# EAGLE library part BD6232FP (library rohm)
H-bridge driver for brush motors Source: http://www.rohm.com/products/databook/motor/pdf/bd623x_series-e.pdf

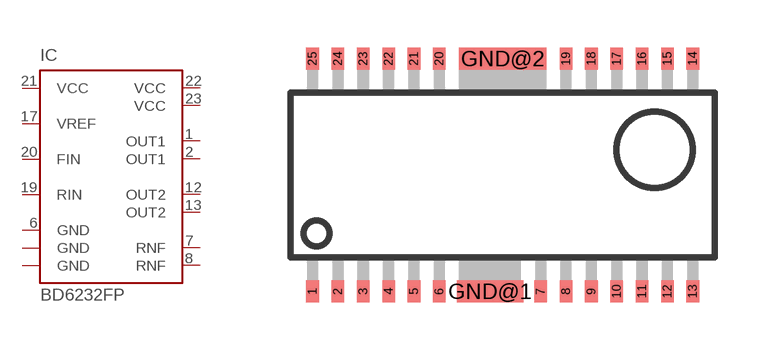
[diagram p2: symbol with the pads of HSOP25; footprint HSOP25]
Designator prefix IC

## BD6232FP (MPN: BD6232FP-E2; OC_FARNELL: 1716266; OC_NEWARK: 15R0531)  [HSOP25]
1  OUT1  out
2  OUT1  out
6  GND  pwr
7  RNF  pas
8  RNF  pas
12  OUT2  out
13  OUT2  out
17  VREF  pas
19  RIN  in
20  FIN  in
21  VCC  pwr
22  VCC  pwr
23  VCC  pwr
GND@1  GND  pwr
GND@2  GND  pwr

## Footprint HSOP25 (pad centres in mm)
HSOP 25 Source: http://www.rohm.com/products/databook/motor/pdf/bd623x_series-e.pdf
smd 0.4 x 0.7: 1 -6,-3.675; 2 -5.2,-3.675; 3 -4.4,-3.675; 4 -3.6,-3.675; 5 -2.8,-3.675; 6 -2,-3.675; 7 1.2,-3.675; 8 2,-3.675; 9 2.8,-3.675; 10 3.6,-3.675; 11 4.4,-3.675; 12 5.2,-3.675; 13 6,-3.675; 14 6,3.675; 15 5.2,3.675; 16 4.4,3.675; 17 3.6,3.675; 18 2.8,3.675; 19 2,3.675; 20 -2,3.675; 21 -2.8,3.675; 22 -3.6,3.675; 23 -4.4,3.675; 24 -5.2,3.675; 25 -6,3.675
smd 2.1 x 0.7: GND@1 -0.4,-3.675
smd 2.75 x 0.7: GND@2 0,3.675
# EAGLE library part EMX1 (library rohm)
General purpose transistors (dual transistors) Two 2SC2412K chips in a EMT or UMT or SMT package. Source: http://www.rohm.com/products/databook/tr/pdf/umx1n.pdf

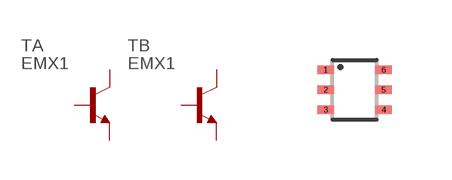
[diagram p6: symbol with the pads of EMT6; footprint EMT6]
Designator prefix T; gates A=NPN B=NPN

## EMX1 (MPN: EMX1T2R; OC_FARNELL: 1680314; OC_NEWARK: 40P3026)  [EMT6]
1  A:E  pas
2  A:B  pas
3  B:C  pas
4  B:E  pas
5  B:B  pas
6  A:C  pas

## Footprint EMT6 (pad centres in mm)
General purpose transistors (dual transistors) EMX1 / UMX1N / IMX1 Source: http://www.rohm.com/products/databook/tr/pdf/umx1n.pdf
smd 0.4 x 0.22: 1 -0.725,0.5; 2 -0.725,0; 3 -0.725,-0.5; 4 0.725,-0.5; 5 0.725,0; 6 0.725,0.5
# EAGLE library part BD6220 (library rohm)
H-bridge drivers (18V max.) Source: http://www.farnell.com/datasheets/389117.pdf

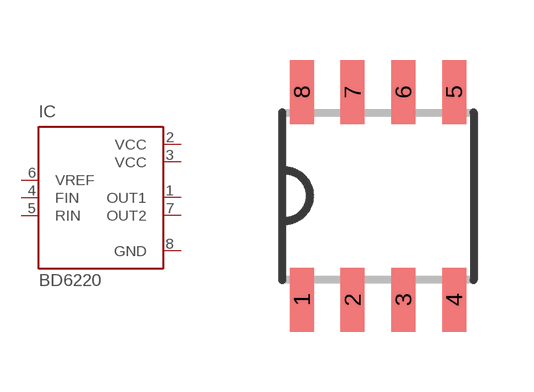
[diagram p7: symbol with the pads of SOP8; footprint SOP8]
Designator prefix IC

## BD6220F  [SOP8]
1  OUT1  out
2  VCC  pwr
3  VCC  pwr
4  FIN  in
5  RIN  in
6  VREF  pas
7  OUT2  out
8  GND  pwr

## Footprint SOP8 (pad centres in mm)
SOP8 Source: http://www.rohm.com/products/databook/motor/pdf/bd623x_series-e.pdf
smd 0.6 x 1.6: 1 -1.905,-2.6; 2 -0.635,-2.6; 3 0.635,-2.6; 4 1.905,-2.6; 5 1.905,2.6; 6 0.635,2.6; 7 -0.635,2.6; 8 -1.905,2.6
